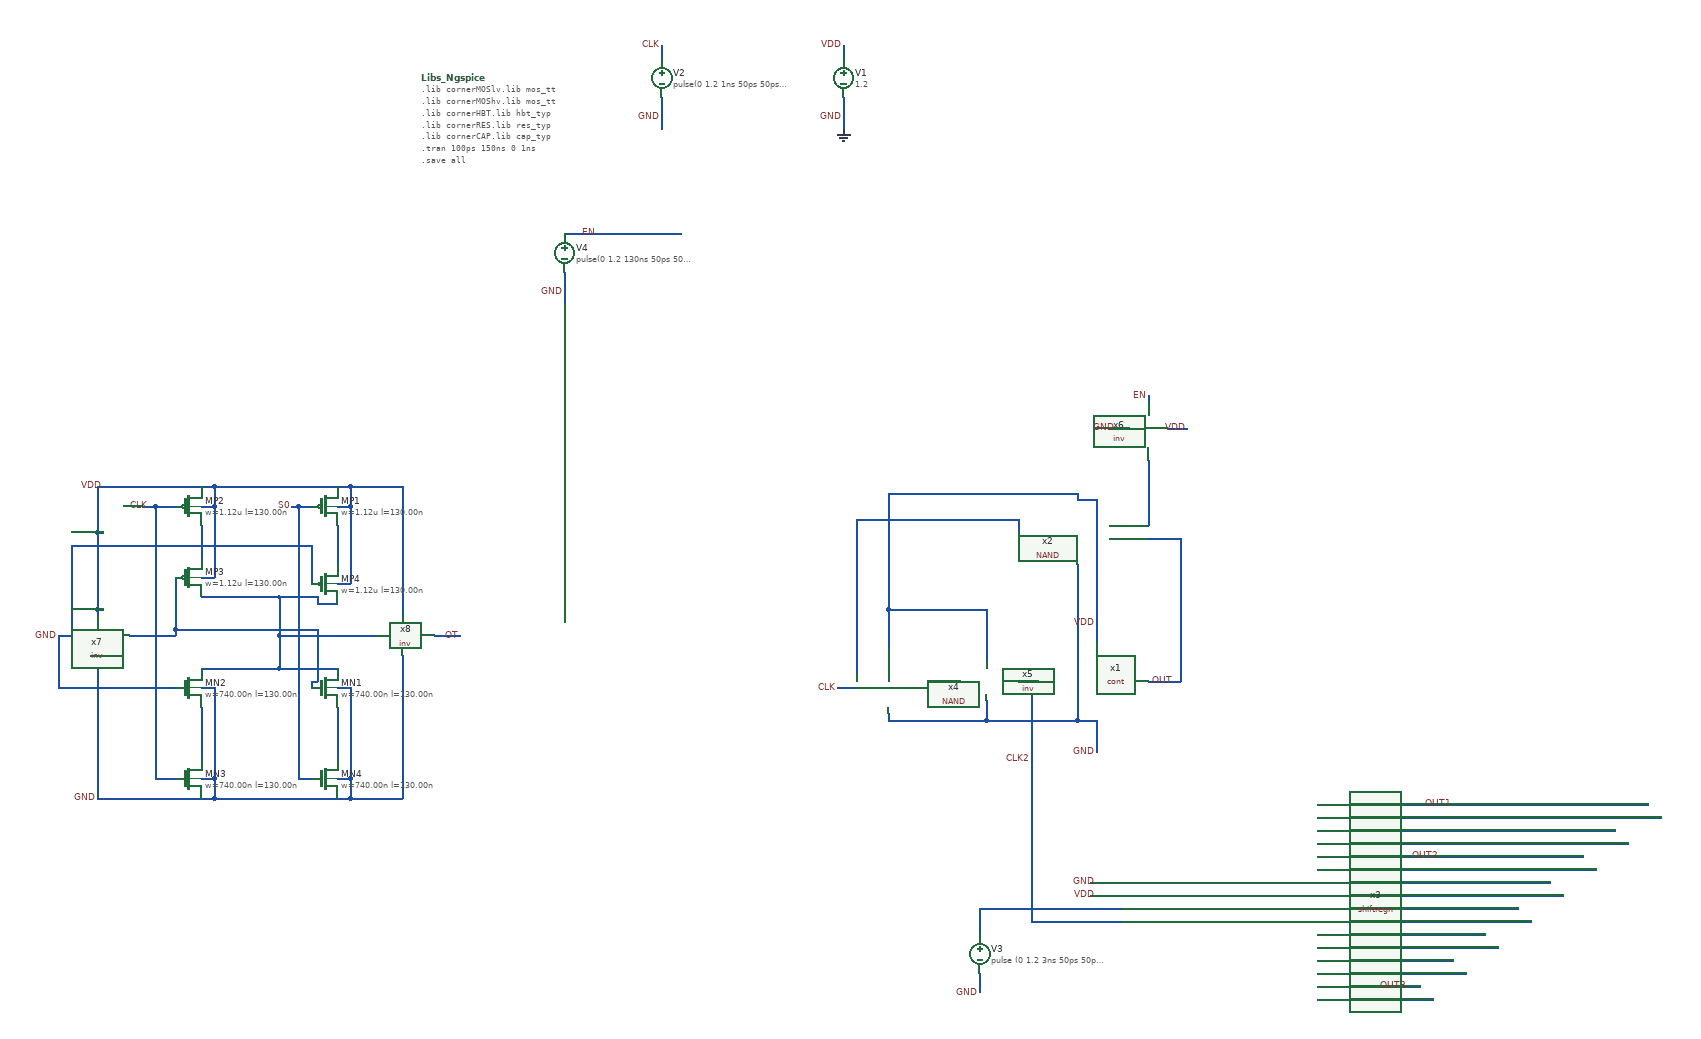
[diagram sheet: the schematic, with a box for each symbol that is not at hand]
v {xschem version=3.4.6 file_version=1.2}
G {}
K {}
V {}
S {}
E {}
P 4 1 -690 180 {}
N 70 210 70 260 {lab=GND}
N 150 150 200 150 {lab=OUT}
N -320 -750 -320 -700 {lab=GND}
N -320 -830 -320 -810 {lab=VDD}
N -750 -540 -570 -540 {lab=EN}
N -600 -750 -600 -700 {lab=GND}
N -600 -830 -600 -810 {lab=CLK}
N 70 -130 70 90 {lab=VDD}
N 40 -130 70 -130 {lab=VDD}
N 40 -30 40 210 {lab=GND}
N 40 210 70 210 {lab=GND}
N 200 -70 200 150 {lab=OUT}
N 90 -70 200 -70 {lab=OUT}
N 90 -90 150 -90 {lab=#net1}
N 150 -190 150 -90 {lab=#net1}
N 410 640 590 640 {lab=#net2}
N 410 620 570 620 {lab=OUT3}
N 410 600 640 600 {lab=#net3}
N 410 580 620 580 {lab=#net4}
N 410 560 690 560 {lab=#net5}
N 410 540 670 540 {lab=#net6}
N 410 520 740 520 {lab=#net7}
N 410 500 720 500 {lab=#net8}
N 410 480 790 480 {lab=#net9}
N 410 460 770 460 {lab=#net10}
N 410 440 840 440 {lab=#net11}
N 410 420 820 420 {lab=OUT2}
N 410 400 890 400 {lab=#net12}
N 410 380 870 380 {lab=#net13}
N 410 360 940 360 {lab=#net14}
N 410 340 920 340 {lab=OUT1}
N 60 460 110 460 {lab=GND}
N 60 480 110 480 {lab=VDD}
N -110 500 110 500 {lab=#net15}
N -110 500 -110 540 {lab=#net15}
N -110 600 -110 630 {lab=GND}
N -160 150 -140 150 {lab=#net16}
N -30 150 -20 150 {lab=CLK2}
N -300 -100 -300 140 {lab=#net17}
N -300 -100 -50 -100 {lab=#net17}
N -50 -100 -50 -80 {lab=#net17}
N -330 160 -300 160 {lab=CLK}
N -30 150 -30 520 {lab=CLK2}
N -50 150 -30 150 {lab=CLK2}
N -30 520 110 520 {lab=CLK2}
N -100 210 40 210 {lab=GND}
N -250 200 -250 210 {lab=GND}
N -250 40 -250 100 {lab=VDD}
N -250 -140 40 -140 {lab=VDD}
N 40 -140 40 -130 {lab=VDD}
N -100 40 -100 120 {lab=VDD}
N -250 40 -100 40 {lab=VDD}
N -250 -140 -250 40 {lab=VDD}
N -100 180 -100 210 {lab=GND}
N -250 210 -100 210 {lab=GND}
N -750 -480 -750 -430 {lab=GND}
N 150 -290 150 -280 {lab=EN}
N 90 -240 120 -240 {lab=GND}
N 180 -240 210 -240 {lab=VDD}
N -1310 -90 -1310 -40 {lab=#net4}
N -1100 -90 -1100 -30 {lab=#net5}
N -1190 130 -1100 130 {lab=#net6}
N -1190 20 -1130 20 {lab=#net6}
N -1130 20 -1130 30 {lab=#net6}
N -1130 30 -1100 30 {lab=#net6}
N -1190 80 -1190 130 {lab=#net6}
N -1310 20 -1190 20 {lab=#net6}
N -1310 130 -1190 130 {lab=#net6}
N -1190 80 -1040 80 {lab=#net6}
N -1190 20 -1190 80 {lab=#net6}
N -1470 -80 -1470 40 {lab=VDD}
N -1470 40 -1470 50 {lab=VDD}
N -1470 -80 -1460 -80 {lab=VDD}
N -1470 -150 -1470 -80 {lab=VDD}
N -1470 40 -1460 40 {lab=VDD}
N -1290 330 -1080 330 {lab=GND}
N -1480 110 -1470 110 {lab=GND}
N -1380 -120 -1350 -120 {lab=CLK}
N -1530 80 -1510 80 {lab=GND}
N -1470 110 -1470 330 {lab=GND}
N -1310 -120 -1290 -120 {lab=VDD}
N -1290 -150 -1290 -120 {lab=VDD}
N -1470 -150 -1290 -150 {lab=VDD}
N -1310 -10 -1290 -10 {lab=VDD}
N -1290 -120 -1290 -10 {lab=VDD}
N -1100 -120 -1080 -120 {lab=VDD}
N -1290 -150 -1080 -150 {lab=VDD}
N -1080 -150 -1080 -120 {lab=VDD}
N -1080 -120 -1080 0 {lab=VDD}
N -1100 0 -1080 0 {lab=VDD}
N -1310 300 -1290 300 {lab=GND}
N -1290 300 -1290 330 {lab=GND}
N -1470 330 -1290 330 {lab=GND}
N -1100 300 -1080 300 {lab=GND}
N -1080 300 -1080 330 {lab=GND}
N -1310 160 -1290 160 {lab=GND}
N -1290 160 -1290 300 {lab=GND}
N -1100 160 -1080 160 {lab=GND}
N -1080 160 -1080 300 {lab=GND}
N -1380 -120 -1380 300 {lab=CLK}
N -1400 -120 -1380 -120 {lab=CLK}
N -1380 300 -1350 300 {lab=CLK}
N -1160 -120 -1140 -120 {lab=S0}
N -1160 -120 -1160 300 {lab=S0}
N -1170 -120 -1160 -120 {lab=S0}
N -1160 300 -1140 300 {lab=S0}
N -1420 80 -1350 80 {lab=#net7}
N -1350 70 -1350 80 {lab=#net7}
N -1350 70 -1130 70 {lab=#net7}
N -1350 -10 -1350 70 {lab=#net7}
N -1130 70 -1130 150 {lab=#net7}
N -1140 150 -1130 150 {lab=#net7}
N -1140 150 -1140 160 {lab=#net7}
N -1140 -60 -1140 0 {lab=GND}
N -1510 -60 -1140 -60 {lab=GND}
N -1510 -60 -1510 80 {lab=GND}
N -1530 160 -1350 160 {lab=GND}
N -1530 80 -1530 160 {lab=GND}
N -1310 190 -1310 270 {lab=#net8}
N -1100 190 -1100 270 {lab=#net9}
N -1000 110 -1000 330 {lab=GND}
N -1080 330 -1000 330 {lab=GND}
N -1000 -150 -1000 50 {lab=VDD}
N -1080 -150 -1000 -150 {lab=VDD}
N -950 80 -910 80 {lab=OT}
C {simulator_commands_shown.sym} -970 -780 0 0 {
name=Libs_Ngspice
simulator=ngspice
only_toplevel=false
value="
.lib cornerMOSlv.lib mos_tt
.lib cornerMOShv.lib mos_tt
.lib cornerHBT.lib hbt_typ
.lib cornerRES.lib res_typ
.lib cornerCAP.lib cap_typ
.tran 100ps 150ns 0 1ns
.save all

"
      }
C {/home/designer/shared/cont.sym} 130 150 0 0 {name=x1}
C {lab_wire.sym} 70 60 0 0 {name=p3 sig_type=std_logic lab=VDD

}
C {lab_wire.sym} 70 260 0 0 {name=p4 sig_type=std_logic lab=GND
}
C {lab_wire.sym} 190 150 0 0 {name=p7 sig_type=std_logic lab=OUT



}
C {vsource.sym} -320 -780 0 0 {name=V1 value=1.2 }
C {gnd.sym} -320 -700 0 0 {name=l1 lab=GND
}
C {lab_wire.sym} -320 -720 0 0 {name=p1 sig_type=std_logic lab=GND
}
C {lab_wire.sym} -320 -830 0 0 {name=p2 sig_type=std_logic lab=VDD

}
C {vsource.sym} -750 -510 0 0 {name=V4 value="pulse(0 1.2 130ns 50ps 50ps 10ns 110ns)"}
C {lab_wire.sym} -600 -830 2 1 {name=p6 sig_type=std_logic lab=CLK



}
C {/home/designer/shared/NAND.sym} -30 10 0 1 {name=x2}
C {lab_wire.sym} -600 -720 0 0 {name=p8 sig_type=std_logic lab=GND
}
C {lab_wire.sym} -700 -540 0 0 {name=p9 sig_type=std_logic lab=EN

}
C {/home/designer/shared/shiftregn.sym} 260 510 0 0 {name=x3}
C {lab_wire.sym} 70 460 0 0 {name=p10 sig_type=std_logic lab=GND
}
C {lab_wire.sym} 70 480 0 0 {name=p11 sig_type=std_logic lab=VDD

}
C {vsource.sym} -110 570 0 0 {name=V3 value="pulse (0 1.2 3ns 50ps 50ps 40ns 80ns)"}
C {lab_wire.sym} -110 630 0 0 {name=p14 sig_type=std_logic lab=GND
}
C {/home/designer/shared/NAND.sym} -180 240 0 0 {name=x4}
C {/home/designer/shared/inv.sym} -60 240 0 0 {name=x5}
C {lab_wire.sym} -330 160 2 1 {name=p5 sig_type=std_logic lab=CLK



}
C {lab_wire.sym} 150 -290 0 0 {name=p12 sig_type=std_logic lab=EN

}
C {lab_wire.sym} 620 340 0 0 {name=p13 sig_type=std_logic lab=OUT1
}
C {lab_wire.sym} 600 420 0 0 {name=p15 sig_type=std_logic lab=OUT2}
C {lab_wire.sym} 550 620 0 0 {name=p17 sig_type=std_logic lab=OUT3}
C {lab_wire.sym} -750 -450 0 0 {name=p16 sig_type=std_logic lab=GND
}
C {vsource.sym} -600 -780 0 0 {name=V2 value="pulse(0 1.2 1ns 50ps 50ps 5ns 10ns)"}
C {/home/designer/shared/inv.sym} 60 -200 1 0 {name=x6}
C {lab_wire.sym} 210 -240 0 0 {name=p18 sig_type=std_logic lab=VDD

}
C {lab_wire.sym} 100 -240 0 0 {name=p19 sig_type=std_logic lab=GND
}
C {lab_wire.sym} -30 270 2 1 {name=p20 sig_type=std_logic lab=CLK2



}
C {lab_wire.sym} -1460 -150 0 0 {name=p21 sig_type=std_logic lab=VDD

}
C {lab_wire.sym} -1470 330 0 0 {name=p22 sig_type=std_logic lab=GND
}
C {lab_wire.sym} -1170 -120 0 0 {name=p23 sig_type=std_logic lab=S0
}
C {lab_wire.sym} -1390 -120 0 0 {name=p24 sig_type=std_logic lab=CLK
}
C {lab_wire.sym} -910 80 0 0 {name=p25 sig_type=std_logic lab=OT}
C {sg13g2_pr/sg13_lv_nmos.sym} -1330 160 0 0 {name=MN2
l=130.00n
w=740.00n
ng=1
m=1
model=sg13_lv_nmos
spiceprefix=X
}
C {sg13g2_pr/sg13_lv_pmos.sym} -1330 -120 0 0 {name=MP2
l=130.00n
w=1.12u
ng=1
m=1
model=sg13_lv_pmos
spiceprefix=X
}
C {/home/designer/shared/inv.sym} -1430 170 0 0 {name=x7}
C {sg13g2_pr/sg13_lv_pmos.sym} -1120 -120 0 0 {name=MP1
l=130.00n
w=1.12u
ng=1
m=1
model=sg13_lv_pmos
spiceprefix=X
}
C {sg13g2_pr/sg13_lv_pmos.sym} -1330 -10 0 0 {name=MP3
l=130.00n
w=1.12u
ng=1
m=1
model=sg13_lv_pmos
spiceprefix=X
}
C {sg13g2_pr/sg13_lv_pmos.sym} -1120 0 0 0 {name=MP4
l=130.00n
w=1.12u
ng=1
m=1
model=sg13_lv_pmos
spiceprefix=X
}
C {sg13g2_pr/sg13_lv_nmos.sym} -1120 160 0 0 {name=MN1
l=130.00n
w=740.00n
ng=1
m=1
model=sg13_lv_nmos
spiceprefix=X
}
C {sg13g2_pr/sg13_lv_nmos.sym} -1330 300 0 0 {name=MN3
l=130.00n
w=740.00n
ng=1
m=1
model=sg13_lv_nmos
spiceprefix=X
}
C {sg13g2_pr/sg13_lv_nmos.sym} -1120 300 0 0 {name=MN4
l=130.00n
w=740.00n
ng=1
m=1
model=sg13_lv_nmos
spiceprefix=X
}
C {/home/designer/shared/inv.sym} -960 170 0 0 {name=x8}
C {lab_wire.sym} -1530 80 0 0 {name=p26 sig_type=std_logic lab=GND

}
